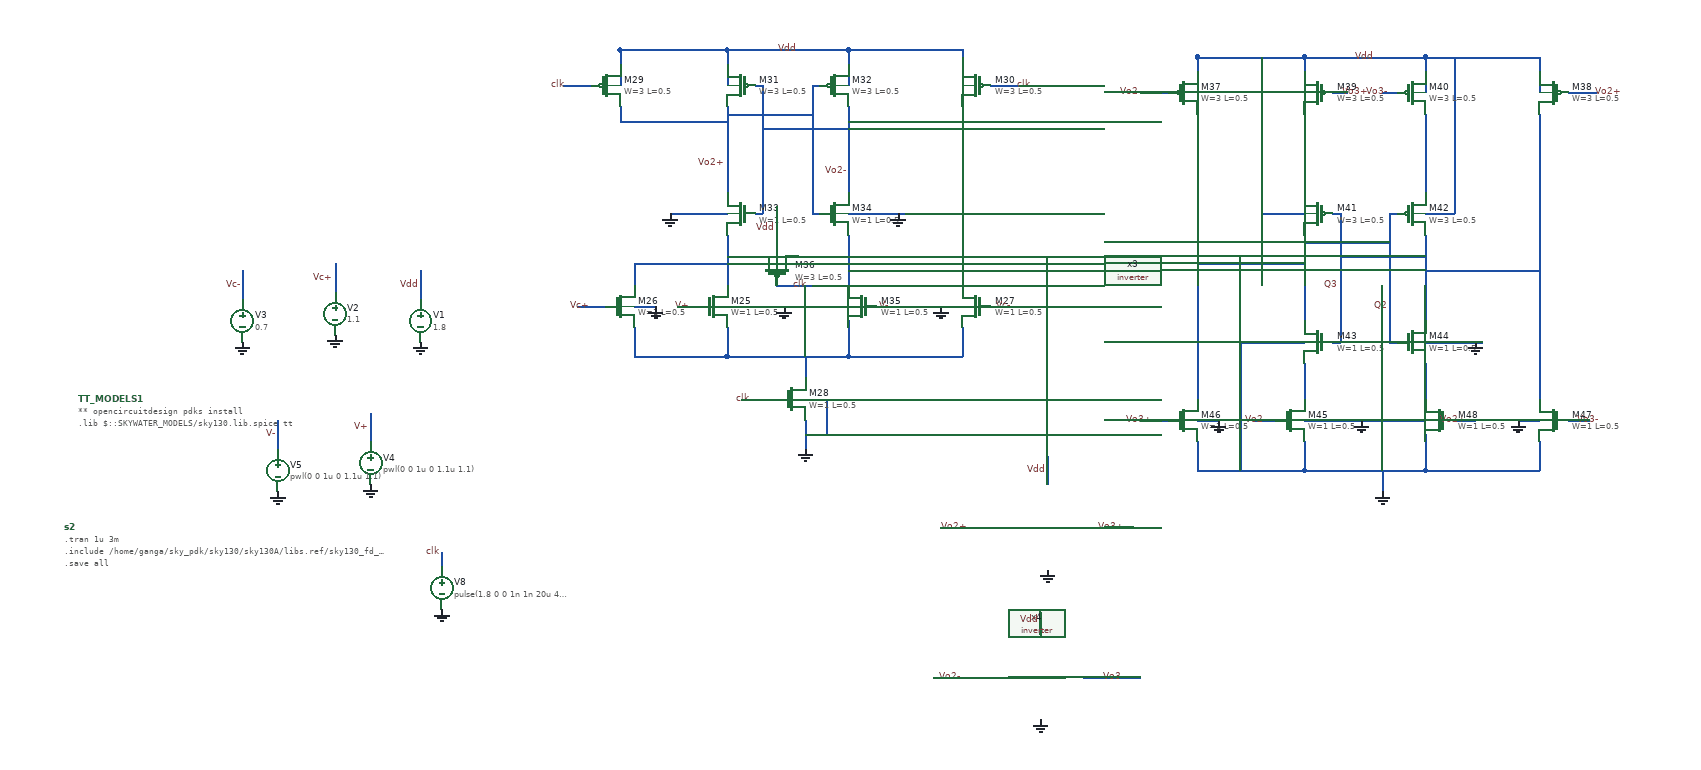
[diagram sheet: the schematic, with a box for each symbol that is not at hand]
v {xschem version=3.4.4 file_version=1.2
}
G {}
K {}
V {}
S {}
E {}
N -1350 -910 -1350 -790 {
lab=Vo2+}
N -1180 -910 -1180 -800 {
lab=Vo2-}
N -1180 -800 -1180 -790 {
lab=Vo2-}
N -1350 -990 -1350 -970 {
lab=Vdd}
N -1350 -990 -1180 -990 {
lab=Vdd}
N -1180 -990 -1180 -970 {
lab=Vdd}
N -1310 -940 -1300 -940 {
lab=Vo2-}
N -1300 -940 -1300 -760 {
lab=Vo2-}
N -1310 -760 -1300 -760 {
lab=Vo2-}
N -1230 -940 -1220 -940 {
lab=Vo2+}
N -1230 -940 -1230 -760 {
lab=Vo2+}
N -1230 -760 -1220 -760 {
lab=Vo2+}
N -1500 -990 -1350 -990 {
lab=Vdd}
N -1500 -990 -1500 -970 {
lab=Vdd}
N -1180 -990 -1020 -990 {
lab=Vdd}
N -1020 -990 -1020 -970 {
lab=Vdd}
N -1500 -910 -1500 -890 {
lab=Vo2+}
N -1500 -890 -1350 -890 {
lab=Vo2+}
N -1020 -910 -1020 -890 {
lab=Vo2-}
N -1180 -890 -1020 -890 {
lab=Vo2-}
N -1350 -900 -1230 -900 {
lab=Vo2+}
N -1300 -880 -1180 -880 {
lab=Vo2-}
N -1350 -730 -1350 -660 {
lab=#net1}
N -1180 -730 -1180 -660 {
lab=#net2}
N -1350 -600 -1350 -560 {
lab=#net3}
N -1350 -560 -1180 -560 {
lab=#net3}
N -1180 -610 -1180 -560 {
lab=#net3}
N -1020 -600 -1020 -560 {
lab=#net3}
N -1180 -560 -1020 -560 {
lab=#net3}
N -1020 -680 -1020 -660 {
lab=#net2}
N -1180 -680 -1020 -680 {
lab=#net2}
N -1480 -600 -1480 -560 {
lab=#net3}
N -1480 -560 -1350 -560 {
lab=#net3}
N -1480 -690 -1480 -660 {
lab=#net1}
N -1480 -690 -1350 -690 {
lab=#net1}
N -1240 -560 -1240 -530 {
lab=#net3}
N -1330 -500 -1280 -500 {
lab=clk}
N -1240 -470 -1240 -430 {
lab=GND}
N -1350 -700 -1310 -700 {
lab=#net1}
N -1250 -700 -1180 -700 {
lab=#net2}
N -1560 -630 -1520 -630 {
lab=Vc+}
N -1420 -630 -1390 -630 {
lab=V+}
N -1140 -630 -1110 -630 {
lab=V-}
N -980 -630 -950 -630 {
lab=Vc-}
N -980 -940 -940 -940 {
lab=clk}
N -1580 -940 -1540 -940 {
lab=clk}
N -1350 -630 -1180 -630 {
lab=GND}
N -1050 -630 -1020 -630 {
lab=GND}
N -1480 -630 -1450 -630 {
lab=GND}
N -1500 -960 -1500 -940 {
lab=Vdd}
N -1350 -960 -1350 -940 {
lab=Vdd}
N -1180 -970 -1180 -950 {
lab=Vdd}
N -1180 -960 -1180 -940 {
lab=Vdd}
N -1020 -980 -1020 -940 {
lab=Vdd}
N -1350 -980 -1350 -940 {
lab=Vdd}
N -1500 -990 -1500 -940 {
lab=Vdd}
N -1180 -760 -1100 -760 {
lab=GND}
N -1430 -760 -1350 -760 {
lab=GND}
N -1280 -770 -1280 -700 {
lab=Vdd}
N -1280 -660 -1230 -660 {
lab=clk}
N -1240 -500 -1210 -500 {
lab=GND}
N -1210 -500 -1210 -450 {
lab=GND}
N -1240 -450 -1210 -450 {
lab=GND}
N -540 -980 -540 -960 {
lab=Vdd}
N -540 -980 -370 -980 {
lab=Vdd}
N -370 -980 -370 -960 {
lab=Vdd}
N -500 -930 -490 -930 {
lab=Vo3+}
N -420 -930 -410 -930 {
lab=Vo3-}
N -690 -980 -540 -980 {
lab=Vdd}
N -690 -980 -690 -960 {
lab=Vdd}
N -370 -980 -210 -980 {
lab=Vdd}
N -210 -980 -210 -960 {
lab=Vdd}
N -690 -900 -690 -880 {
lab=Q2}
N -210 -900 -210 -880 {
lab=Q3}
N -170 -930 -130 -930 {
lab=Vo2+}
N -770 -930 -730 -930 {
lab=Vo2-}
N -690 -950 -690 -930 {
lab=Vdd}
N -540 -950 -540 -930 {
lab=Vdd}
N -370 -960 -370 -940 {
lab=Vdd}
N -370 -950 -370 -930 {
lab=Vdd}
N -210 -970 -210 -930 {
lab=Vdd}
N -540 -970 -540 -930 {
lab=Vdd}
N -690 -980 -690 -930 {
lab=Vdd}
N -370 -900 -370 -810 {
lab=#net4}
N -540 -730 -540 -610 {
lab=Q2}
N -370 -730 -370 -620 {
lab=Q3}
N -370 -620 -370 -610 {
lab=Q3}
N -540 -810 -540 -790 {
lab=#net5}
N -370 -810 -370 -790 {
lab=#net4}
N -500 -760 -490 -760 {
lab=Q3}
N -490 -760 -490 -580 {
lab=Q3}
N -500 -580 -490 -580 {
lab=Q3}
N -420 -760 -410 -760 {
lab=Q2}
N -420 -760 -420 -580 {
lab=Q2}
N -420 -580 -410 -580 {
lab=Q2}
N -540 -720 -420 -720 {
lab=Q2}
N -490 -700 -370 -700 {
lab=Q3}
N -370 -580 -290 -580 {
lab=GND}
N -540 -900 -540 -810 {
lab=#net5}
N -540 -440 -540 -400 {
lab=GND}
N -540 -400 -370 -400 {
lab=GND}
N -370 -450 -370 -400 {
lab=GND}
N -210 -440 -210 -400 {
lab=GND}
N -370 -400 -210 -400 {
lab=GND}
N -210 -520 -210 -500 {
lab=Q3}
N -690 -440 -690 -400 {
lab=GND}
N -670 -400 -540 -400 {
lab=GND}
N -690 -530 -690 -500 {
lab=Q2}
N -430 -400 -430 -370 {
lab=GND}
N -770 -470 -730 -470 {
lab=Vo3+}
N -610 -470 -580 -470 {
lab=Vo2-}
N -330 -470 -300 -470 {
lab=Vo2+}
N -170 -470 -140 -470 {
lab=Vo3-}
N -540 -470 -370 -470 {
lab=GND}
N -240 -470 -210 -470 {
lab=GND}
N -690 -470 -660 -470 {
lab=GND}
N -540 -550 -540 -500 {
lab=#net6}
N -370 -550 -370 -500 {
lab=#net7}
N -690 -880 -690 -530 {
lab=Q2}
N -210 -880 -210 -530 {
lab=Q3}
N -210 -530 -210 -520 {
lab=Q3}
N -690 -400 -670 -400 {
lab=GND}
N -430 -930 -420 -930 {
lab=Vo3-}
N -490 -930 -480 -930 {
lab=Vo3+}
N -690 -690 -540 -690 {
lab=Q2}
N -370 -680 -210 -680 {
lab=Q3}
N -1050 -320 -970 -320 {
lab=Vo2+}
N -840 -320 -780 -320 {
lab=Vo3+}
N -1060 -110 -980 -110 {
lab=Vo2-}
N -850 -110 -770 -110 {
lab=Vo3-}
N -600 -760 -540 -760 {
lab=Vdd}
N -600 -980 -600 -760 {
lab=Vdd}
N -370 -760 -330 -760 {
lab=Vdd}
N -330 -980 -330 -760 {
lab=Vdd}
N -630 -580 -540 -580 {
lab=GND}
N -630 -580 -630 -400 {
lab=GND}
N -900 -420 -900 -380 {
lab=Vdd}
N -910 -200 -910 -170 {
lab=Vdd}
N -1780 -680 -1780 -640 {
lab=Vdd}
N -1900 -690 -1900 -650 {
lab=Vc+}
N -2030 -680 -2030 -640 {
lab=Vc-}
N -1850 -480 -1850 -440 {
lab=V+}
N -1980 -470 -1980 -430 {
lab=V-}
N -1750 -285 -1750 -265 {
lab=clk}
C {sky130_fd_pr/nfet_01v8.sym} -1370 -630 0 0 {name=M25
L=0.5
W=1
nf=1 
mult=1
ad="'int((nf+1)/2) * W/nf * 0.29'" 
pd="'2*int((nf+1)/2) * (W/nf + 0.29)'"
as="'int((nf+2)/2) * W/nf * 0.29'" 
ps="'2*int((nf+2)/2) * (W/nf + 0.29)'"
nrd="'0.29 / W'" nrs="'0.29 / W'"
sa=0 sb=0 sd=0
model=nfet_01v8
spiceprefix=X
}
C {sky130_fd_pr/nfet_01v8.sym} -1500 -630 0 0 {name=M26
L=0.5
W=1
nf=1 
mult=1
ad="'int((nf+1)/2) * W/nf * 0.29'" 
pd="'2*int((nf+1)/2) * (W/nf + 0.29)'"
as="'int((nf+2)/2) * W/nf * 0.29'" 
ps="'2*int((nf+2)/2) * (W/nf + 0.29)'"
nrd="'0.29 / W'" nrs="'0.29 / W'"
sa=0 sb=0 sd=0
model=nfet_01v8
spiceprefix=X
}
C {sky130_fd_pr/nfet_01v8.sym} -1000 -630 0 1 {name=M27
L=0.5
W=1
nf=1 
mult=1
ad="'int((nf+1)/2) * W/nf * 0.29'" 
pd="'2*int((nf+1)/2) * (W/nf + 0.29)'"
as="'int((nf+2)/2) * W/nf * 0.29'" 
ps="'2*int((nf+2)/2) * (W/nf + 0.29)'"
nrd="'0.29 / W'" nrs="'0.29 / W'"
sa=0 sb=0 sd=0
model=nfet_01v8
spiceprefix=X
}
C {sky130_fd_pr/nfet_01v8.sym} -1260 -500 0 0 {name=M28
L=0.5
W=1
nf=1 
mult=1
ad="'int((nf+1)/2) * W/nf * 0.29'" 
pd="'2*int((nf+1)/2) * (W/nf + 0.29)'"
as="'int((nf+2)/2) * W/nf * 0.29'" 
ps="'2*int((nf+2)/2) * (W/nf + 0.29)'"
nrd="'0.29 / W'" nrs="'0.29 / W'"
sa=0 sb=0 sd=0
model=nfet_01v8
spiceprefix=X
}
C {sky130_fd_pr/pfet_01v8.sym} -1520 -940 0 0 {name=M29
L=0.5
W=3
nf=1
mult=1
ad="'int((nf+1)/2) * W/nf * 0.29'" 
pd="'2*int((nf+1)/2) * (W/nf + 0.29)'"
as="'int((nf+2)/2) * W/nf * 0.29'" 
ps="'2*int((nf+2)/2) * (W/nf + 0.29)'"
nrd="'0.29 / W'" nrs="'0.29 / W'"
sa=0 sb=0 sd=0
model=pfet_01v8
spiceprefix=X
}
C {sky130_fd_pr/pfet_01v8.sym} -1000 -940 0 1 {name=M30
L=0.5
W=3
nf=1
mult=1
ad="'int((nf+1)/2) * W/nf * 0.29'" 
pd="'2*int((nf+1)/2) * (W/nf + 0.29)'"
as="'int((nf+2)/2) * W/nf * 0.29'" 
ps="'2*int((nf+2)/2) * (W/nf + 0.29)'"
nrd="'0.29 / W'" nrs="'0.29 / W'"
sa=0 sb=0 sd=0
model=pfet_01v8
spiceprefix=X
}
C {sky130_fd_pr/pfet_01v8.sym} -1330 -940 0 1 {name=M31
L=0.5
W=3
nf=1
mult=1
ad="'int((nf+1)/2) * W/nf * 0.29'" 
pd="'2*int((nf+1)/2) * (W/nf + 0.29)'"
as="'int((nf+2)/2) * W/nf * 0.29'" 
ps="'2*int((nf+2)/2) * (W/nf + 0.29)'"
nrd="'0.29 / W'" nrs="'0.29 / W'"
sa=0 sb=0 sd=0
model=pfet_01v8
spiceprefix=X
}
C {sky130_fd_pr/pfet_01v8.sym} -1200 -940 0 0 {name=M32
L=0.5
W=3
nf=1
mult=1
ad="'int((nf+1)/2) * W/nf * 0.29'" 
pd="'2*int((nf+1)/2) * (W/nf + 0.29)'"
as="'int((nf+2)/2) * W/nf * 0.29'" 
ps="'2*int((nf+2)/2) * (W/nf + 0.29)'"
nrd="'0.29 / W'" nrs="'0.29 / W'"
sa=0 sb=0 sd=0
model=pfet_01v8
spiceprefix=X
}
C {sky130_fd_pr/nfet_01v8.sym} -1330 -760 0 1 {name=M33
L=0.5
W=1
nf=1 
mult=1
ad="'int((nf+1)/2) * W/nf * 0.29'" 
pd="'2*int((nf+1)/2) * (W/nf + 0.29)'"
as="'int((nf+2)/2) * W/nf * 0.29'" 
ps="'2*int((nf+2)/2) * (W/nf + 0.29)'"
nrd="'0.29 / W'" nrs="'0.29 / W'"
sa=0 sb=0 sd=0
model=nfet_01v8
spiceprefix=X
}
C {sky130_fd_pr/nfet_01v8.sym} -1200 -760 0 0 {name=M34
L=0.5
W=1
nf=1 
mult=1
ad="'int((nf+1)/2) * W/nf * 0.29'" 
pd="'2*int((nf+1)/2) * (W/nf + 0.29)'"
as="'int((nf+2)/2) * W/nf * 0.29'" 
ps="'2*int((nf+2)/2) * (W/nf + 0.29)'"
nrd="'0.29 / W'" nrs="'0.29 / W'"
sa=0 sb=0 sd=0
model=nfet_01v8
spiceprefix=X
}
C {sky130_fd_pr/nfet_01v8.sym} -1160 -630 0 1 {name=M35
L=0.5
W=1
nf=1 
mult=1
ad="'int((nf+1)/2) * W/nf * 0.29'" 
pd="'2*int((nf+1)/2) * (W/nf + 0.29)'"
as="'int((nf+2)/2) * W/nf * 0.29'" 
ps="'2*int((nf+2)/2) * (W/nf + 0.29)'"
nrd="'0.29 / W'" nrs="'0.29 / W'"
sa=0 sb=0 sd=0
model=nfet_01v8
spiceprefix=X
}
C {devices/gnd.sym} -1240 -430 0 0 {name=l18 lab=GND}
C {devices/gnd.sym} -1450 -630 0 0 {name=l19 lab=GND}
C {devices/gnd.sym} -1270 -630 0 0 {name=l20 lab=GND}
C {devices/gnd.sym} -1050 -630 0 0 {name=l21 lab=GND}
C {devices/gnd.sym} -1110 -760 0 0 {name=l22 lab=GND}
C {devices/gnd.sym} -1430 -760 0 0 {name=l23 lab=GND}
C {devices/lab_wire.sym} -1250 -990 0 0 {name=p27 sig_type=std_logic lab=Vdd
}
C {sky130_fd_pr/pfet_01v8.sym} -1280 -680 1 1 {name=M36
L=0.5
W=3
nf=1
mult=1
ad="'int((nf+1)/2) * W/nf * 0.29'" 
pd="'2*int((nf+1)/2) * (W/nf + 0.29)'"
as="'int((nf+2)/2) * W/nf * 0.29'" 
ps="'2*int((nf+2)/2) * (W/nf + 0.29)'"
nrd="'0.29 / W'" nrs="'0.29 / W'"
sa=0 sb=0 sd=0
model=pfet_01v8
spiceprefix=X
}
C {devices/lab_wire.sym} -1280 -740 1 0 {name=p36 sig_type=std_logic lab=Vdd
}
C {devices/lab_wire.sym} -950 -630 0 0 {name=p37 sig_type=std_logic lab=Vc-
}
C {devices/lab_wire.sym} -1540 -630 0 0 {name=p38 sig_type=std_logic lab=Vc+
}
C {devices/lab_wire.sym} -1400 -630 0 0 {name=p39 sig_type=std_logic lab=V+
}
C {devices/lab_wire.sym} -1120 -630 0 0 {name=p40 sig_type=std_logic lab=V-
}
C {devices/lab_pin.sym} -1315 -500 0 0 {name=p42 sig_type=std_logic lab=clk
}
C {devices/lab_pin.sym} -1235 -660 0 0 {name=p43 sig_type=std_logic lab=clk
}
C {devices/lab_pin.sym} -1575 -940 0 0 {name=p44 sig_type=std_logic lab=clk
}
C {devices/lab_pin.sym} -945 -940 0 1 {name=p45 sig_type=std_logic lab=clk
}
C {devices/lab_wire.sym} -1350 -830 0 0 {name=p46 sig_type=std_logic lab=Vo2+
}
C {devices/lab_wire.sym} -1180 -820 0 0 {name=p47 sig_type=std_logic lab=Vo2-
}
C {sky130_fd_pr/pfet_01v8.sym} -710 -930 0 0 {name=M37
L=0.5
W=3
nf=1
mult=1
ad="'int((nf+1)/2) * W/nf * 0.29'" 
pd="'2*int((nf+1)/2) * (W/nf + 0.29)'"
as="'int((nf+2)/2) * W/nf * 0.29'" 
ps="'2*int((nf+2)/2) * (W/nf + 0.29)'"
nrd="'0.29 / W'" nrs="'0.29 / W'"
sa=0 sb=0 sd=0
model=pfet_01v8
spiceprefix=X
}
C {sky130_fd_pr/pfet_01v8.sym} -190 -930 0 1 {name=M38
L=0.5
W=3
nf=1
mult=1
ad="'int((nf+1)/2) * W/nf * 0.29'" 
pd="'2*int((nf+1)/2) * (W/nf + 0.29)'"
as="'int((nf+2)/2) * W/nf * 0.29'" 
ps="'2*int((nf+2)/2) * (W/nf + 0.29)'"
nrd="'0.29 / W'" nrs="'0.29 / W'"
sa=0 sb=0 sd=0
model=pfet_01v8
spiceprefix=X
}
C {sky130_fd_pr/pfet_01v8.sym} -520 -930 0 1 {name=M39
L=0.5
W=3
nf=1
mult=1
ad="'int((nf+1)/2) * W/nf * 0.29'" 
pd="'2*int((nf+1)/2) * (W/nf + 0.29)'"
as="'int((nf+2)/2) * W/nf * 0.29'" 
ps="'2*int((nf+2)/2) * (W/nf + 0.29)'"
nrd="'0.29 / W'" nrs="'0.29 / W'"
sa=0 sb=0 sd=0
model=pfet_01v8
spiceprefix=X
}
C {sky130_fd_pr/pfet_01v8.sym} -390 -930 0 0 {name=M40
L=0.5
W=3
nf=1
mult=1
ad="'int((nf+1)/2) * W/nf * 0.29'" 
pd="'2*int((nf+1)/2) * (W/nf + 0.29)'"
as="'int((nf+2)/2) * W/nf * 0.29'" 
ps="'2*int((nf+2)/2) * (W/nf + 0.29)'"
nrd="'0.29 / W'" nrs="'0.29 / W'"
sa=0 sb=0 sd=0
model=pfet_01v8
spiceprefix=X
}
C {devices/lab_wire.sym} -440 -980 0 0 {name=p48 sig_type=std_logic lab=Vdd
}
C {devices/lab_pin.sym} -765 -930 0 0 {name=p49 sig_type=std_logic lab=Vo2-
}
C {devices/lab_pin.sym} -135 -930 0 1 {name=p50 sig_type=std_logic lab=Vo2+
}
C {sky130_fd_pr/pfet_01v8.sym} -520 -760 0 1 {name=M41
L=0.5
W=3
nf=1
mult=1
ad="'int((nf+1)/2) * W/nf * 0.29'" 
pd="'2*int((nf+1)/2) * (W/nf + 0.29)'"
as="'int((nf+2)/2) * W/nf * 0.29'" 
ps="'2*int((nf+2)/2) * (W/nf + 0.29)'"
nrd="'0.29 / W'" nrs="'0.29 / W'"
sa=0 sb=0 sd=0
model=pfet_01v8
spiceprefix=X
}
C {sky130_fd_pr/pfet_01v8.sym} -390 -760 0 0 {name=M42
L=0.5
W=3
nf=1
mult=1
ad="'int((nf+1)/2) * W/nf * 0.29'" 
pd="'2*int((nf+1)/2) * (W/nf + 0.29)'"
as="'int((nf+2)/2) * W/nf * 0.29'" 
ps="'2*int((nf+2)/2) * (W/nf + 0.29)'"
nrd="'0.29 / W'" nrs="'0.29 / W'"
sa=0 sb=0 sd=0
model=pfet_01v8
spiceprefix=X
}
C {sky130_fd_pr/nfet_01v8.sym} -520 -580 0 1 {name=M43
L=0.5
W=1
nf=1 
mult=1
ad="'int((nf+1)/2) * W/nf * 0.29'" 
pd="'2*int((nf+1)/2) * (W/nf + 0.29)'"
as="'int((nf+2)/2) * W/nf * 0.29'" 
ps="'2*int((nf+2)/2) * (W/nf + 0.29)'"
nrd="'0.29 / W'" nrs="'0.29 / W'"
sa=0 sb=0 sd=0
model=nfet_01v8
spiceprefix=X
}
C {sky130_fd_pr/nfet_01v8.sym} -390 -580 0 0 {name=M44
L=0.5
W=1
nf=1 
mult=1
ad="'int((nf+1)/2) * W/nf * 0.29'" 
pd="'2*int((nf+1)/2) * (W/nf + 0.29)'"
as="'int((nf+2)/2) * W/nf * 0.29'" 
ps="'2*int((nf+2)/2) * (W/nf + 0.29)'"
nrd="'0.29 / W'" nrs="'0.29 / W'"
sa=0 sb=0 sd=0
model=nfet_01v8
spiceprefix=X
}
C {devices/gnd.sym} -300 -580 0 0 {name=l26 lab=GND}
C {sky130_fd_pr/nfet_01v8.sym} -560 -470 0 0 {name=M45
L=0.5
W=1
nf=1 
mult=1
ad="'int((nf+1)/2) * W/nf * 0.29'" 
pd="'2*int((nf+1)/2) * (W/nf + 0.29)'"
as="'int((nf+2)/2) * W/nf * 0.29'" 
ps="'2*int((nf+2)/2) * (W/nf + 0.29)'"
nrd="'0.29 / W'" nrs="'0.29 / W'"
sa=0 sb=0 sd=0
model=nfet_01v8
spiceprefix=X
}
C {sky130_fd_pr/nfet_01v8.sym} -710 -470 0 0 {name=M46
L=0.5
W=1
nf=1 
mult=1
ad="'int((nf+1)/2) * W/nf * 0.29'" 
pd="'2*int((nf+1)/2) * (W/nf + 0.29)'"
as="'int((nf+2)/2) * W/nf * 0.29'" 
ps="'2*int((nf+2)/2) * (W/nf + 0.29)'"
nrd="'0.29 / W'" nrs="'0.29 / W'"
sa=0 sb=0 sd=0
model=nfet_01v8
spiceprefix=X
}
C {sky130_fd_pr/nfet_01v8.sym} -190 -470 0 1 {name=M47
L=0.5
W=1
nf=1 
mult=1
ad="'int((nf+1)/2) * W/nf * 0.29'" 
pd="'2*int((nf+1)/2) * (W/nf + 0.29)'"
as="'int((nf+2)/2) * W/nf * 0.29'" 
ps="'2*int((nf+2)/2) * (W/nf + 0.29)'"
nrd="'0.29 / W'" nrs="'0.29 / W'"
sa=0 sb=0 sd=0
model=nfet_01v8
spiceprefix=X
}
C {sky130_fd_pr/nfet_01v8.sym} -350 -470 0 1 {name=M48
L=0.5
W=1
nf=1 
mult=1
ad="'int((nf+1)/2) * W/nf * 0.29'" 
pd="'2*int((nf+1)/2) * (W/nf + 0.29)'"
as="'int((nf+2)/2) * W/nf * 0.29'" 
ps="'2*int((nf+2)/2) * (W/nf + 0.29)'"
nrd="'0.29 / W'" nrs="'0.29 / W'"
sa=0 sb=0 sd=0
model=nfet_01v8
spiceprefix=X
}
C {devices/gnd.sym} -660 -470 0 0 {name=l27 lab=GND}
C {devices/gnd.sym} -460 -470 0 0 {name=l28 lab=GND}
C {devices/gnd.sym} -240 -470 0 0 {name=l29 lab=GND}
C {devices/lab_wire.sym} -590 -470 0 0 {name=p51 sig_type=std_logic lab=Vo2-
}
C {devices/lab_wire.sym} -310 -470 0 0 {name=p52 sig_type=std_logic lab=Vo2+

}
C {devices/gnd.sym} -430 -370 0 0 {name=l30 lab=GND}
C {devices/lab_wire.sym} -1010 -320 0 0 {name=p53 sig_type=std_logic lab=Vo2+
}
C {devices/lab_wire.sym} -1020 -110 0 0 {name=p54 sig_type=std_logic lab=Vo2-
}
C {devices/lab_wire.sym} -790 -320 0 0 {name=p55 sig_type=std_logic lab=Vo3+
}
C {devices/lab_wire.sym} -790 -110 0 0 {name=p56 sig_type=std_logic lab=Vo3-
}
C {devices/lab_wire.sym} -490 -930 0 1 {name=p57 sig_type=std_logic lab=Vo3+
}
C {devices/lab_wire.sym} -420 -930 0 0 {name=p58 sig_type=std_logic lab=Vo3-
}
C {devices/lab_wire.sym} -750 -470 0 0 {name=p59 sig_type=std_logic lab=Vo3+
}
C {devices/lab_wire.sym} -160 -470 0 1 {name=p60 sig_type=std_logic lab=Vo3-
}
C {devices/lab_wire.sym} -490 -660 0 0 {name=p61 sig_type=std_logic lab=Q3
}
C {devices/lab_wire.sym} -420 -630 0 0 {name=p62 sig_type=std_logic lab=Q2
}
C {inverter.sym} -820 -320 0 0 {name=x3}
C {inverter.sym} -830 -110 0 0 {name=x4}
C {devices/gnd.sym} -910 -50 0 0 {name=l24 lab=GND}
C {devices/gnd.sym} -900 -260 0 0 {name=l25 lab=GND}
C {devices/lab_wire.sym} -900 -400 0 0 {name=p24 sig_type=std_logic lab=Vdd
}
C {devices/lab_wire.sym} -910 -190 0 0 {name=p41 sig_type=std_logic lab=Vdd
}
C {devices/vsource.sym} -1780 -610 0 0 {name=V1 value=1.8}
C {devices/gnd.sym} -1780 -580 0 0 {name=l8 lab=GND}
C {devices/lab_wire.sym} -1780 -660 0 0 {name=p1 sig_type=std_logic lab=Vdd
}
C {devices/vsource.sym} -1900 -620 0 0 {name=V2 value=1.1}
C {devices/gnd.sym} -1900 -590 0 0 {name=l7 lab=GND}
C {devices/lab_wire.sym} -1900 -670 0 0 {name=p22 sig_type=std_logic lab=Vc+
}
C {devices/vsource.sym} -2030 -610 0 0 {name=V3 value=0.7}
C {devices/gnd.sym} -2030 -580 0 0 {name=l9 lab=GND}
C {devices/lab_wire.sym} -2030 -660 0 0 {name=p4 sig_type=std_logic lab=Vc-
}
C {devices/vsource.sym} -1850 -410 0 0 {name=V4 value="pwl(0 0 1u 0 1.1u 1.1)"}
C {devices/gnd.sym} -1850 -380 0 0 {name=l10 lab=GND}
C {devices/lab_wire.sym} -1850 -460 0 0 {name=p7 sig_type=std_logic lab=V+
}
C {devices/vsource.sym} -1980 -400 0 0 {name=V5 value="pwl(0 0 1u 0 1.1u 1.1)"}
C {devices/gnd.sym} -1980 -370 0 0 {name=l11 lab=GND}
C {devices/lab_wire.sym} -1980 -450 0 0 {name=p8 sig_type=std_logic lab=V-
}
C {devices/vsource.sym} -1750 -235 0 0 {name=V8 value="pulse(1.8 0 0 1n 1n 20u 40u)"}
C {devices/gnd.sym} -1750 -205 0 0 {name=l12 lab=GND}
C {devices/lab_pin.sym} -1750 -285 1 0 {name=p25 sig_type=std_logic lab=clk
}
C {devices/code.sym} -2260 -500 0 0 {name=TT_MODELS1
only_toplevel=true
format="tcleval( @value )"
value="
** opencircuitdesign pdks install
.lib $::SKYWATER_MODELS/sky130.lib.spice tt

"
spice_ignore=false}
C {devices/code_shown.sym} -2280 -320 0 0 {name=s2 only_toplevel=false 
value=".tran 1u 3m
.include /home/ganga/sky_pdk/sky130/sky130A/libs.ref/sky130_fd_sc_hd/spice/sky130_fd_sc_hd.spice 
.save all" }
